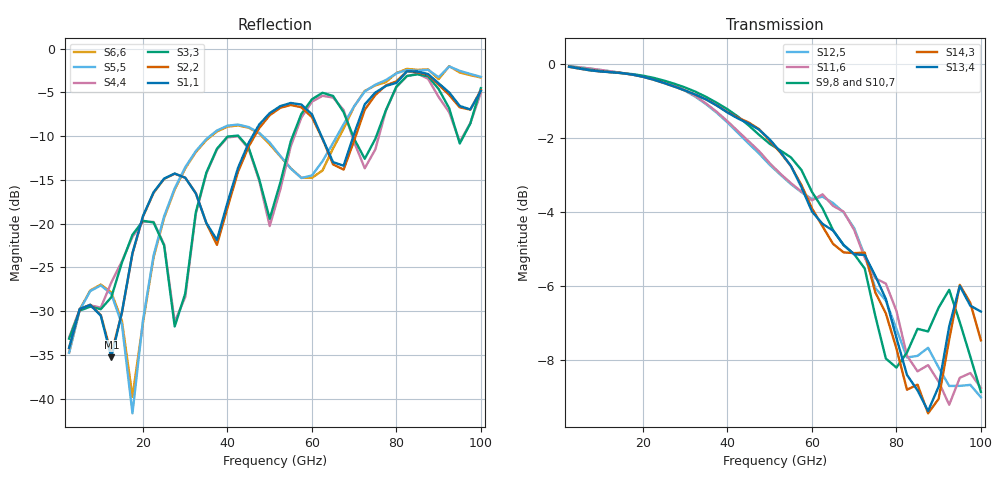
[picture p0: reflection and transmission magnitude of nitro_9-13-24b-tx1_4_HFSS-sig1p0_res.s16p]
! File created by SignalIntegrity v1.5.1: Signal and Power Integrity Tools
! https://github.com/Nubis-Communications/SignalIntegrity
# MHz S MA R 50.0
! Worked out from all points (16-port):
!   40 points, 2.5 GHz to 100 GHz, reference 50 ohm
!   strongest paths, dB at 2.5 GHz, 27.5 GHz, 52.5 GHz, 77.5 GHz, 100 GHz:
!     S13,4: -0.1, -0.6, -2.4, -6.3, -6.7
!     S14,3: -0.1, -0.6, -2.4, -6.7, -7.5
!     S9,8: -0.1, -0.5, -2.3, -8.0, -8.9
!     S10,7: -0.1, -0.5, -2.4, -8.0, -8.6
!     S11,6: -0.1, -0.6, -3.0, -5.9, -8.7
!     S12,5: -0.1, -0.6, -3.0, -6.4, -9.0
!   lowest |S11| = -35.3 dB at 12.5 GHz (marker M1), VSWR 1.04, Z = 49.1 - j1.42 ohm
!   |S11| at or under -10 dB: start of sweep to 45.94 GHz; 62.25 GHz to 69.81 GHz (7.567 GHz wide, 11.5 % of centre)
